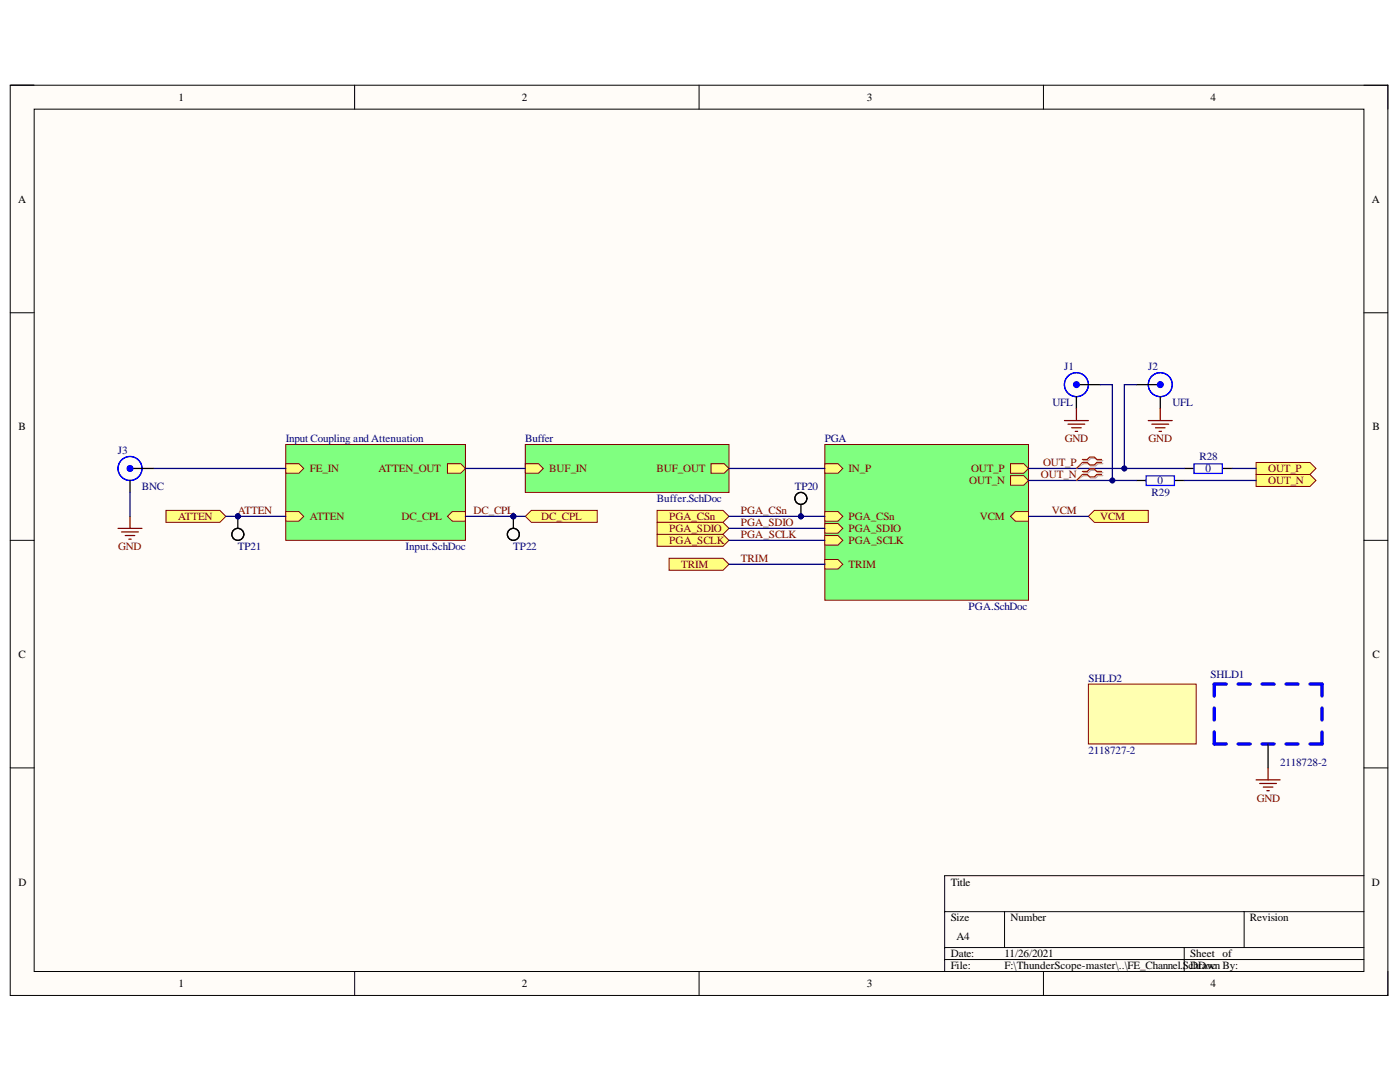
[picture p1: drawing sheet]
<svg xmlns="http://www.w3.org/2000/svg" width="279mm" height="216mm" viewBox="0 0 279 216" stroke-linecap="round" stroke-linejoin="round" font-family="sans-serif">
<defs><g id="words">
<g font-size="2.2">
<text x="35.6" y="20.1">1</text>
<text x="104.1" y="20.1">2</text>
<text x="173" y="20.1">3</text>
<text x="241.6" y="20.1">4</text>
<text x="3.6" y="40.4">A</text>
<text x="273.8" y="40.4">A</text>
<text x="3.7" y="85.8">B</text>
<text x="273.9" y="85.8">B</text>
<text x="3.7" y="131.3">C</text>
<text x="273.9" y="131.3">C</text>
<text x="3.7" y="176.7">D</text>
<text x="189.7" y="176.7">Title</text>
<text x="273.8" y="176.7">D</text>
<text x="189.7" y="183.8">Size</text>
<text x="201.7" y="183.8">Number</text>
<text x="249.4" y="183.8">Revision</text>
<text x="189.7" y="191">Date:</text>
<text x="190.9" y="187.5">A4</text>
<text x="200.5" y="191">11/26/2021</text>
<text x="237.5" y="191">Sheet of</text>
<text x="35.6" y="197">1</text>
<text x="104.1" y="197">2</text>
<text x="173" y="197">3</text>
<text x="189.7" y="193.4">File:</text>
<text x="200.5" y="193.4">F:\ThunderScope-master\..\FE_Channel.ScDrawn By:</text>
<text x="238.1" y="193.4">hDoc</text>
<text x="241.6" y="197">4</text>
</g>
<g font-size="2.2" fill="#000080">
<text x="212.4" y="73.9">J1</text>
<text x="229.1" y="73.9">J2</text>
<text x="210" y="81.1">UFL</text>
<text x="234" y="81.1">UFL</text>
<text x="57" y="88.3">Input Coupling and Attenuation</text>
<text x="104.8" y="88.3">Buffer</text>
<text x="164.6" y="88.3">PGA</text>
<text x="23.5" y="90.7">J3</text>
<text x="239.4" y="91.8">R28</text>
<text x="240.6" y="94.2">0</text>
<text x="28.3" y="97.8">BNC</text>
<text x="131.1" y="100.2">Buffer.SchDoc</text>
<text x="158.6" y="97.8">TP20</text>
<text x="229.8" y="99">R29</text>
<text x="231" y="96.7">0</text>
<text x="47.5" y="109.8">TP21</text>
<text x="80.9" y="109.8">Input.SchDoc</text>
<text x="102.4" y="109.8">TP22</text>
<text x="193.3" y="121.7">PGA.SchDoc</text>
<text x="217.2" y="136.1">SHLD2</text>
<text x="241.6" y="135.4">SHLD1</text>
<text x="217.2" y="150.4">2118727-2</text>
<text x="255.5" y="152.8">2118728-2</text>
</g>
<g font-size="2.2" fill="#800000">
<text x="212.5" y="88.3">GND</text>
<text x="229.2" y="88.3">GND</text>
<text x="61.8" y="94.2">FE_IN</text>
<text x="75.5" y="94.2">ATTEN_OUT</text>
<text x="109.6" y="94.2">BUF_IN</text>
<text x="131" y="94.2">BUF_OUT</text>
<text x="169.3" y="94.2">IN_P</text>
<text x="193.8" y="94.2">OUT_P</text>
<text x="207.7" y="95.5">OUT_N</text>
<text x="208.2" y="93">OUT_P</text>
<text x="253.1" y="94.2">OUT_P</text>
<text x="193.4" y="96.7">OUT_N</text>
<text x="253.1" y="96.7">OUT_N</text>
<text x="35.5" y="103.8">ATTEN</text>
<text x="47.5" y="102.6">ATTEN</text>
<text x="61.8" y="103.8">ATTEN</text>
<text x="80.1" y="103.8">DC_CPL</text>
<text x="94.5" y="102.6">DC_CPL</text>
<text x="108" y="103.8">DC_CPL</text>
<text x="133.6" y="103.8">PGA_CSn</text>
<text x="133.6" y="106.2">PGA_SDIO</text>
<text x="147.9" y="102.6">PGA_CSn</text>
<text x="147.9" y="107.4">PGA_SCLK</text>
<text x="147.9" y="105">PGA_SDIO</text>
<text x="169.3" y="106.2">PGA_SDIO</text>
<text x="169.3" y="103.8">PGA_CSn</text>
<text x="195.6" y="103.8">VCM</text>
<text x="209.9" y="102.6">VCM</text>
<text x="219.6" y="103.8">VCM</text>
<text x="23.6" y="109.8">GND</text>
<text x="133.6" y="108.6">PGA_SCLK</text>
<text x="135.9" y="113.4">TRIM</text>
<text x="147.9" y="112.1">TRIM</text>
<text x="169.3" y="108.6">PGA_SCLK</text>
<text x="169.3" y="113.4">TRIM</text>
<text x="250.8" y="160">GND</text>
</g>
</g></defs>
<path d="M2 17h275v181.6h-275z" fill-rule="evenodd" fill="#fffcf8"/>
<path d="M2 17h275v181.6h-275z" fill="none" stroke="#000" stroke-width=".2"/>
<path d="M6.8 21.8h265.4v172.1h-265.4z" fill-rule="evenodd" fill="#fffcf8"/>
<g fill="none" stroke="#000" stroke-width=".2">
<path d="M2 17h4.8M70.8 17v4.8M139.5 17v4.8M208.2 17v4.8M272.2 17h4.8v4.8M6.8 21.8h265.4v172.1h-265.4zM2 62.4h4.8M272.2 62.4h4.8M2 107.8h4.8M272.2 107.8h4.8M2 153.2h4.8M272.2 153.2h4.8"/>
<path d="M272.2 174.7h-83.7v19.2M70.8 193.9v4.7M139.5 193.9v4.7M188.5 181.9h83.7M188.5 189.1h83.7M188.5 191.5h83.7M200.5 181.9v7.2M208.2 193.9v4.7M236.3 189.1v4.8M248.3 181.9v7.2M277 193.9v4.7"/>
</g>
<path d="M23.6 105.4h4.7M24.3 106.1h3.3M25 106.9h1.9M25.7 107.6h.5M25.9 103v2.4" fill="none" stroke="#800000" stroke-width=".25"/>
<circle cx="25.9" cy="93.5" r="2.39" fill="none" stroke="#00f" stroke-width=".25"/>
<path d="M25.9 93.5h4.8M25.9 95.9v2.4" fill="none" stroke="#000" stroke-width=".25"/>
<circle cx="25.9" cy="93.5" r=".6" fill="#00f"/>
<circle cx="25.9" cy="93.5" r=".6" fill="none" stroke="#00f" stroke-width=".2"/>
<path d="M57 88.7h35.9v19.1h-35.9z" fill-rule="evenodd" fill="#80ff80"/>
<path d="M57 88.7h35.9v19.1h-35.9z" fill="none" stroke="#800000" stroke-width=".2"/>
<path d="M57 102.1h2.7l.9 .9-.9 1h-2.7z" fill-rule="evenodd" fill="#ffff80"/>
<path d="M57 102.1h2.7l.9 .9-.9 1h-2.7z" fill="none" stroke="#800000" stroke-width=".2"/>
<path d="M57 92.5h2.7l.9 1-.9 .9h-2.7z" fill-rule="evenodd" fill="#ffff80"/>
<path d="M57 92.5h2.7l.9 1-.9 .9h-2.7z" fill="none" stroke="#800000" stroke-width=".2"/>
<path d="M89.3 92.5h2.6l1 1-1 .9h-2.6z" fill-rule="evenodd" fill="#ffff80"/>
<path d="M89.3 92.5h2.6l1 1-1 .9h-2.6z" fill="none" stroke="#800000" stroke-width=".2"/>
<path d="M89.3 103l1-.9h2.6v1.9h-2.6z" fill-rule="evenodd" fill="#ffff80"/>
<path d="M89.3 103l1-.9h2.6v1.9h-2.6z" fill="none" stroke="#800000" stroke-width=".2"/>
<path d="M104.8 88.7h40.7v9.6h-40.7z" fill-rule="evenodd" fill="#80ff80"/>
<path d="M104.8 88.7h40.7v9.6h-40.7z" fill="none" stroke="#800000" stroke-width=".2"/>
<path d="M104.8 92.5h2.7l.9 1-.9 .9h-2.7z" fill-rule="evenodd" fill="#ffff80"/>
<path d="M104.8 92.5h2.7l.9 1-.9 .9h-2.7z" fill="none" stroke="#800000" stroke-width=".2"/>
<path d="M141.9 92.5h2.6l1 1-1 .9h-2.6z" fill-rule="evenodd" fill="#ffff80"/>
<path d="M141.9 92.5h2.6l1 1-1 .9h-2.6z" fill="none" stroke="#800000" stroke-width=".2"/>
<path d="M164.6 88.7h40.7v31.1h-40.7z" fill-rule="evenodd" fill="#80ff80"/>
<path d="M164.6 88.7h40.7v31.1h-40.7z" fill="none" stroke="#800000" stroke-width=".2"/>
<path d="M164.6 92.5h2.6l1 1-1 .9h-2.6z" fill-rule="evenodd" fill="#ffff80"/>
<path d="M164.6 92.5h2.6l1 1-1 .9h-2.6z" fill="none" stroke="#800000" stroke-width=".2"/>
<path d="M201.7 94.9h2.6l1 1-1 .9h-2.6z" fill-rule="evenodd" fill="#ffff80"/>
<path d="M201.7 94.9h2.6l1 1-1 .9h-2.6z" fill="none" stroke="#800000" stroke-width=".2"/>
<path d="M164.6 104.5h2.6l1 .9-1 1h-2.6z" fill-rule="evenodd" fill="#ffff80"/>
<path d="M164.6 104.5h2.6l1 .9-1 1h-2.6z" fill="none" stroke="#800000" stroke-width=".2"/>
<path d="M201.7 92.5h2.6l1 1-1 .9h-2.6z" fill-rule="evenodd" fill="#ffff80"/>
<path d="M201.7 92.5h2.6l1 1-1 .9h-2.6z" fill="none" stroke="#800000" stroke-width=".2"/>
<path d="M202.6 102.1h2.7v1.9h-2.7l-.9-1z" fill-rule="evenodd" fill="#ffff80"/>
<path d="M202.6 102.1h2.7v1.9h-2.7l-.9-1z" fill="none" stroke="#800000" stroke-width=".2"/>
<path d="M164.6 106.9h2.6l1 .9-1 1h-2.6z" fill-rule="evenodd" fill="#ffff80"/>
<path d="M164.6 106.9h2.6l1 .9-1 1h-2.6z" fill="none" stroke="#800000" stroke-width=".2"/>
<path d="M164.6 102.1h2.6l1 .9-1 1h-2.6z" fill-rule="evenodd" fill="#ffff80"/>
<path d="M164.6 102.1h2.6l1 .9-1 1h-2.6z" fill="none" stroke="#800000" stroke-width=".2"/>
<path d="M164.6 111.6h2.6l1 1-1 1h-2.6z" fill-rule="evenodd" fill="#ffff80"/>
<path d="M164.6 111.6h2.6l1 1-1 1h-2.6z" fill="none" stroke="#800000" stroke-width=".2"/>
<circle cx="47.5" cy="103" r=".48" fill="#000080"/>
<circle cx="47.5" cy="103" r=".48" fill="none" stroke="#000080" stroke-width=".2"/>
<circle cx="102.5" cy="103" r=".48" fill="#000080"/>
<circle cx="102.5" cy="103" r=".48" fill="none" stroke="#000080" stroke-width=".2"/>
<path d="M250.7 92.3h10.7l1.2 1.2-1.2 1.2h-10.7z" fill-rule="evenodd" fill="#ffff80"/>
<path d="M250.7 92.3h10.7l1.2 1.2-1.2 1.2h-10.7z" fill="none" stroke="#800000" stroke-width=".2"/>
<path d="M250.7 94.7h10.7l1.2 1.2-1.2 1.2h-10.7z" fill-rule="evenodd" fill="#ffff80"/>
<path d="M250.7 94.7h10.7l1.2 1.2-1.2 1.2h-10.7z" fill="none" stroke="#800000" stroke-width=".2"/>
<path d="M33.1 101.8h10.8l1.2 1.2-1.2 1.2h-10.8z" fill-rule="evenodd" fill="#ffff80"/>
<path d="M33.1 101.8h10.8l1.2 1.2-1.2 1.2h-10.8z" fill="none" stroke="#800000" stroke-width=".2"/>
<path d="M104.8 103l1.2-1.2h13.2v2.4h-13.2z" fill-rule="evenodd" fill="#ffff80"/>
<path d="M104.8 103l1.2-1.2h13.2v2.4h-13.2z" fill="none" stroke="#800000" stroke-width=".2"/>
<path d="M131.1 101.8h13.2l1.2 1.2-1.2 1.2h-13.2z" fill-rule="evenodd" fill="#ffff80"/>
<path d="M131.1 101.8h13.2l1.2 1.2-1.2 1.2h-13.2z" fill="none" stroke="#800000" stroke-width=".2"/>
<path d="M131.1 106.6h13.2l1.2 1.2-1.2 1.2h-13.2z" fill-rule="evenodd" fill="#ffff80"/>
<path d="M131.1 106.6h13.2l1.2 1.2-1.2 1.2h-13.2z" fill="none" stroke="#800000" stroke-width=".2"/>
<path d="M131.1 104.2h13.2l1.2 1.2-1.2 1.2h-13.2z" fill-rule="evenodd" fill="#ffff80"/>
<path d="M131.1 104.2h13.2l1.2 1.2-1.2 1.2h-13.2z" fill="none" stroke="#800000" stroke-width=".2"/>
<path d="M133.5 111.4h10.8l1.2 1.2-1.2 1.2h-10.8z" fill-rule="evenodd" fill="#ffff80"/>
<path d="M133.5 111.4h10.8l1.2 1.2-1.2 1.2h-10.8z" fill="none" stroke="#800000" stroke-width=".2"/>
<path d="M217.2 103l1.2-1.2h10.8v2.4h-10.8z" fill-rule="evenodd" fill="#ffff80"/>
<path d="M217.2 103l1.2-1.2h10.8v2.4h-10.8z" fill="none" stroke="#800000" stroke-width=".2"/>
<path d="M214.8 76.8h4.8M214.8 79.1v2.4M226.8 95.9h1.9M234.5 95.9h1.8M236.3 93.5h1.9M244 93.5h1.9" fill="none" stroke="#000" stroke-width=".25"/>
<g fill="none" stroke="#00f" stroke-width=".25">
<path d="M228.7 95h5.7v1.9h-5.7zM238.3 92.6h5.6v1.9h-5.6z"/>
<circle cx="214.8" cy="76.8" r="2.39"/>
</g>
<circle cx="214.8" cy="76.7" r=".6" fill="#00f"/>
<circle cx="214.8" cy="76.7" r=".6" fill="none" stroke="#00f" stroke-width=".2"/>
<path d="M212.4 83.9h4.8M213.1 84.6h3.4M213.9 85.4h1.9M214.6 86.1h.5M214.8 81.5v2.4" fill="none" stroke="#800000" stroke-width=".25"/>
<circle cx="231.6" cy="76.8" r="2.39" fill="none" stroke="#00f" stroke-width=".25"/>
<path d="M226.8 76.8h4.8M231.6 79.1v2.4" fill="none" stroke="#000" stroke-width=".25"/>
<circle cx="231.6" cy="76.7" r=".6" fill="#00f"/>
<circle cx="231.6" cy="76.7" r=".6" fill="none" stroke="#00f" stroke-width=".2"/>
<path d="M229.2 83.9h4.7M229.9 84.6h3.3M230.6 85.4h1.9M231.3 86.1h.5M231.6 81.5v2.4" fill="none" stroke="#800000" stroke-width=".25"/>
<circle cx="47.5" cy="103" r=".48" fill="#000080"/>
<circle cx="47.5" cy="103" r=".48" fill="none" stroke="#000080" stroke-width=".2"/>
<path d="M47.5 103v2.4" fill="none" stroke="#000" stroke-width=".25"/>
<circle cx="47.5" cy="103" r=".48" fill="#000080"/>
<circle cx="47.5" cy="103" r=".48" fill="none" stroke="#000080" stroke-width=".2"/>
<circle cx="47.5" cy="106.6" r="1.19" fill="none" stroke="#000" stroke-width=".25"/>
<circle cx="102.5" cy="103" r=".48" fill="#000080"/>
<circle cx="102.5" cy="103" r=".48" fill="none" stroke="#000080" stroke-width=".2"/>
<path d="M102.5 103v2.4" fill="none" stroke="#000" stroke-width=".25"/>
<circle cx="102.5" cy="103" r=".48" fill="#000080"/>
<circle cx="102.5" cy="103" r=".48" fill="none" stroke="#000080" stroke-width=".2"/>
<circle cx="102.5" cy="106.6" r="1.19" fill="none" stroke="#000" stroke-width=".25"/>
<circle cx="159.8" cy="103" r=".48" fill="#000080"/>
<circle cx="159.8" cy="103" r=".48" fill="none" stroke="#000080" stroke-width=".2"/>
<path d="M159.8 100.6v2.4" fill="none" stroke="#000" stroke-width=".25"/>
<circle cx="159.8" cy="103" r=".48" fill="#000080"/>
<circle cx="159.8" cy="103" r=".48" fill="none" stroke="#000080" stroke-width=".2"/>
<g fill="none" stroke="#000" stroke-width=".25">
<path d="M253.1 148.4v4.8"/>
<circle cx="159.8" cy="99.5" r="1.19"/>
</g>
<path d="M244.7 136.5h-2.4v2.4M247.1 136.5h2.4M251.9 136.5h2.4M256.7 136.5h2.3M261.4 136.5h2.4v2.4M242.3 141.3v2.4M242.3 146.1v2.3h2.4M247.1 148.4h2.4M251.9 148.4h2.4M256.7 148.4h2.3M263.8 146.1v2.3h-2.4M263.8 141.3v2.4" fill="none" stroke="#00f" stroke-width=".67"/>
<path d="M250.7 155.6h4.8M251.4 156.3h3.3M252.1 157.1h1.9M252.8 157.8h.5M253.1 153.2v2.4" fill="none" stroke="#800000" stroke-width=".25"/>
<path d="M30.7 93.5h26.3M45.1 103h11.9" fill="none" stroke="#000080" stroke-width=".25"/>
<circle cx="47.5" cy="103" r=".48" fill="#000080"/>
<circle cx="47.5" cy="103" r=".48" fill="none" stroke="#000080" stroke-width=".2"/>
<path d="M92.9 103h11.9" fill="none" stroke="#000080" stroke-width=".25"/>
<circle cx="102.5" cy="103" r=".48" fill="#000080"/>
<circle cx="102.5" cy="103" r=".48" fill="none" stroke="#000080" stroke-width=".2"/>
<path d="M25.9 98.3v4.7M92.9 93.5h11.9M145.5 93.5h19.1M145.5 103h19.1M145.5 107.8h19.1M145.5 105.4h19.1" fill="none" stroke="#000080" stroke-width=".25"/>
<circle cx="159.8" cy="103" r=".48" fill="#000080"/>
<circle cx="159.8" cy="103" r=".48" fill="none" stroke="#000080" stroke-width=".2"/>
<path d="M205.3 93.5h31M145.5 112.6h19.1M205.3 103h11.9" fill="none" stroke="#000080" stroke-width=".25"/>
<circle cx="224.4" cy="93.5" r=".48" fill="#000080"/>
<circle cx="224.4" cy="93.5" r=".48" fill="none" stroke="#000080" stroke-width=".2"/>
<path d="M205.3 95.9h21.5M245.9 93.5h4.8" fill="none" stroke="#000080" stroke-width=".25"/>
<circle cx="222" cy="95.9" r=".48" fill="#000080"/>
<circle cx="222" cy="95.9" r=".48" fill="none" stroke="#000080" stroke-width=".2"/>
<path d="M219.6 76.8h2.4v19.1M236.3 95.9h14.4" fill="none" stroke="#000080" stroke-width=".25"/>
<circle cx="222" cy="95.9" r=".48" fill="#000080"/>
<circle cx="222" cy="95.9" r=".48" fill="none" stroke="#000080" stroke-width=".2"/>
<path d="M226.8 76.8h-2.4v16.7" fill="none" stroke="#000080" stroke-width=".25"/>
<circle cx="224.4" cy="93.5" r=".48" fill="#000080"/>
<circle cx="224.4" cy="93.5" r=".48" fill="none" stroke="#000080" stroke-width=".2"/>
<path d="M216.3 91.9h.9l.5-.5h.9l.5 .5h1M216.3 92.5h.9l.5 .5h.9l.5-.5h1M216.3 94.3h.9l.5-.5h.9l.5 .5h1M216.3 94.9h.9l.5 .5h.9l.5-.5h1" fill="none" stroke="#d0a19e" stroke-width=".25"/>
<path d="M216.3 92.5l-1.5 1M216.3 94.9l-1.5 1" fill="none" stroke="#d0a19e" stroke-width=".2"/>
<path d="M216 91.7h1l.5-.5h.9l.5 .5h.9M216 92.3h1l.5 .5h.9l.5-.5h.9M216 94.1h1l.5-.5h.9l.5 .5h.9M216 94.7h1l.5 .5h.9l.5-.5h.9" fill="none" stroke="#f00" stroke-width=".25"/>
<path d="M216 92.3l-1.2 1.2M216 94.7l-1.2 1.2" fill="none" stroke="#f00" stroke-width=".2"/>
<path d="M217.2 136.5h21.5v11.9h-21.5z" fill-rule="evenodd" fill="#ffffb0"/>
<path d="M217.2 136.5h21.5v11.9h-21.5z" fill="none" stroke="#800000" stroke-width=".2"/>
<use href="#words"/>
</svg>
